One B-rep face of a CAD part: STEP entity #222.
In plain terms, the planar face has unit normal (1, 0, 0).
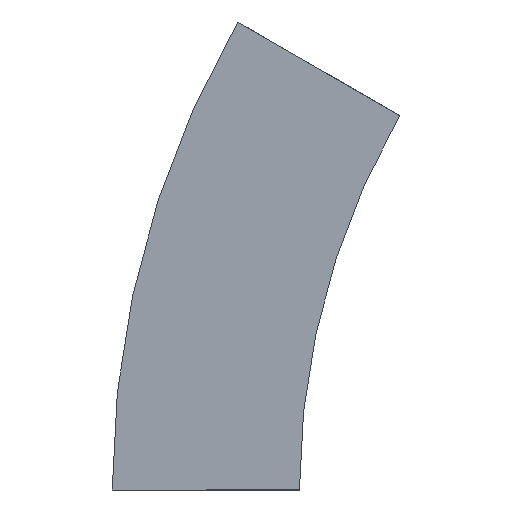
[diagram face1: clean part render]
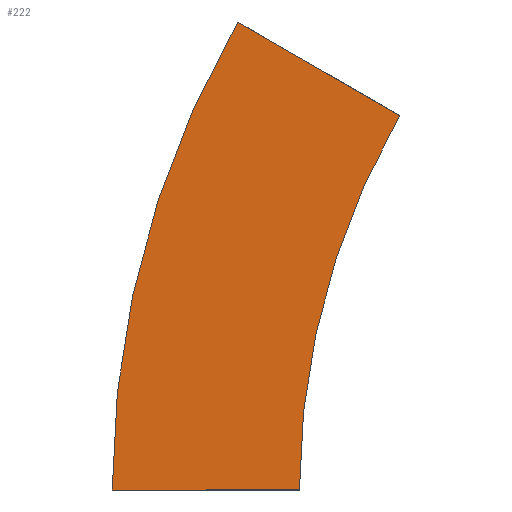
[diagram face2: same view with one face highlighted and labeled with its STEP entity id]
Its self-contained STEP definition (entity closure, numbers rounded to 3 decimals):
#5 = DIRECTION ( 'NONE',  ( 0., 1., 0. ) ) ;
#7 = EDGE_CURVE ( 'NONE', #540, #97, #134, .T. ) ;
#44 = CARTESIAN_POINT ( 'NONE',  ( 0., -40.192, 150. ) ) ;
#66 = CARTESIAN_POINT ( 'NONE',  ( 0., -40.192, 150. ) ) ;
#90 = EDGE_LOOP ( 'NONE', ( #194, #93, #358, #495 ) ) ;
#92 = VECTOR ( 'NONE', #394, 1000. ) ;
#93 = ORIENTED_EDGE ( 'NONE', *, *, #408, .F. ) ;
#95 = LINE ( 'NONE', #44, #267 ) ;
#97 = VERTEX_POINT ( 'NONE', #66 ) ;
#99 = LINE ( 'NONE', #521, #92 ) ;
#118 = DIRECTION ( 'NONE',  ( 0., 1., 0. ) ) ;
#120 = FACE_OUTER_BOUND ( 'NONE', #90, .T. ) ;
#134 = CIRCLE ( 'NONE', #426, 300. ) ;
#194 = ORIENTED_EDGE ( 'NONE', *, *, #485, .T. ) ;
#218 = DIRECTION ( 'NONE',  ( 1., 0., 0. ) ) ;
#222 = ADVANCED_FACE ( 'NONE', ( #120 ), #560, .T. ) ;
#242 = DIRECTION ( 'NONE',  ( 1., 0., 0. ) ) ;
#244 = VERTEX_POINT ( 'NONE', #300 ) ;
#256 = DIRECTION ( 'NONE',  ( 0., 0., -1. ) ) ;
#267 = VECTOR ( 'NONE', #432, 1000. ) ;
#273 = CARTESIAN_POINT ( 'NONE',  ( 0., -300., 0. ) ) ;
#292 = CARTESIAN_POINT ( 'NONE',  ( 0., 0., 0. ) ) ;
#300 = CARTESIAN_POINT ( 'NONE',  ( 0., 75., 0. ) ) ;
#301 = CARTESIAN_POINT ( 'NONE',  ( 0., 0., 0. ) ) ;
#358 = ORIENTED_EDGE ( 'NONE', *, *, #7, .F. ) ;
#367 = CIRCLE ( 'NONE', #514, 375. ) ;
#394 = DIRECTION ( 'NONE',  ( 0., 1., 0. ) ) ;
#408 = EDGE_CURVE ( 'NONE', #97, #483, #95, .T. ) ;
#426 = AXIS2_PLACEMENT_3D ( 'NONE', #448, #242, #118 ) ;
#428 = CARTESIAN_POINT ( 'NONE',  ( 0., 24.76, 187.5 ) ) ;
#432 = DIRECTION ( 'NONE',  ( 0., 0.866, 0.5 ) ) ;
#448 = CARTESIAN_POINT ( 'NONE',  ( 0., -300., 0. ) ) ;
#468 = AXIS2_PLACEMENT_3D ( 'NONE', #301, #218, #256 ) ;
#482 = DIRECTION ( 'NONE',  ( 1., 0., 0. ) ) ;
#483 = VERTEX_POINT ( 'NONE', #428 ) ;
#485 = EDGE_CURVE ( 'NONE', #244, #483, #367, .T. ) ;
#495 = ORIENTED_EDGE ( 'NONE', *, *, #499, .T. ) ;
#499 = EDGE_CURVE ( 'NONE', #540, #244, #99, .T. ) ;
#514 = AXIS2_PLACEMENT_3D ( 'NONE', #273, #482, #5 ) ;
#521 = CARTESIAN_POINT ( 'NONE',  ( 0., 0., 0. ) ) ;
#540 = VERTEX_POINT ( 'NONE', #292 ) ;
#560 = PLANE ( 'NONE',  #468 ) ;
